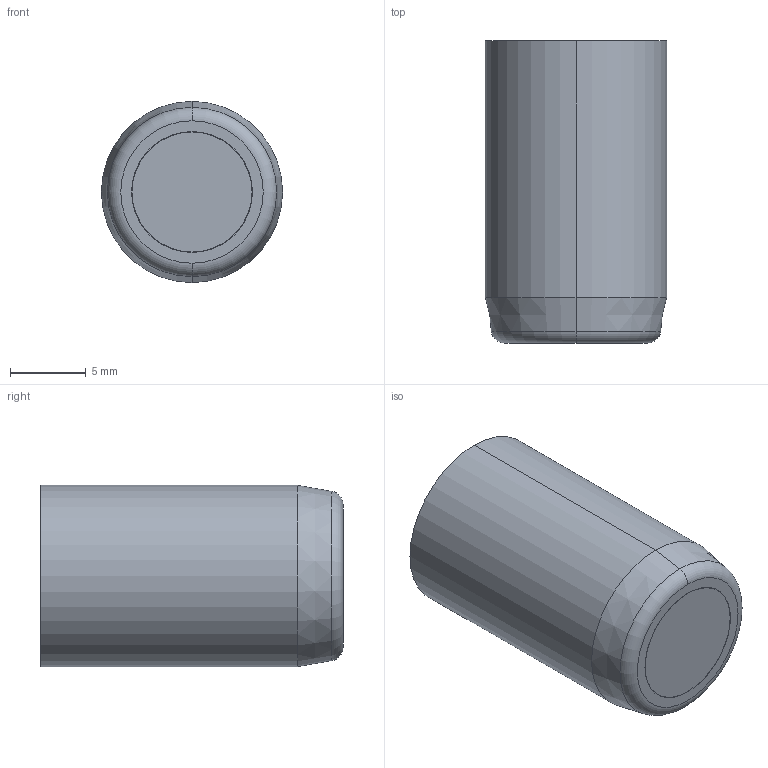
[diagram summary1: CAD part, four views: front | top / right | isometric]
STEP (ISO 10303-21) file: header records copied from the file, then geometry measured from it (millimetres).
FILE_DESCRIPTION (( 'STEP AP214' ), '1' );
FILE_NAME ('FA 126708-20.STEP', '2013-10-01T09:54:28', ( '' ), ( '' ), 'SwSTEP 2.0', 'SolidWorks 2011', '' );
FILE_SCHEMA (( 'AUTOMOTIVE_DESIGN' ));
Length unit declared in the file: millimetre
Products named in the file (6): FA 126700-2 comprimido; FA 126700-1; FA 126708-20; FA 126700-3; IA 6717SF; FA 126708-20-1
Assembly tree (5 placements, depth 2):
  FA 126708-20
    FA 126700-1
    FA 126700-3
    FA 126700-2 comprimido
    FA 126708-20-1
    IA 6717SF
Bounding box: 12 x 20 x 12 mm (x, y, z)
Volume: 2014.6 mm3; surface area: 2188.1 mm2
Topology: 5 solids, 5 shells, 334 faces, 860 edges, 560 vertices
Faces by surface type: plane 149, cylinder 145, cone 24, torus 12, bspline 2, sphere 2
Entity records: 11804 total; most frequent: CARTESIAN_POINT 3130, DIRECTION 1844, ORIENTED_EDGE 1716, EDGE_CURVE 858, AXIS2_PLACEMENT_3D 682, VERTEX_POINT 560, LINE 480, VECTOR 480
One B-rep face of a CAD part: STEP entity #173.
In plain terms, the cylindrical face has radius 6 mm (diameter 12 mm), a partial arc.
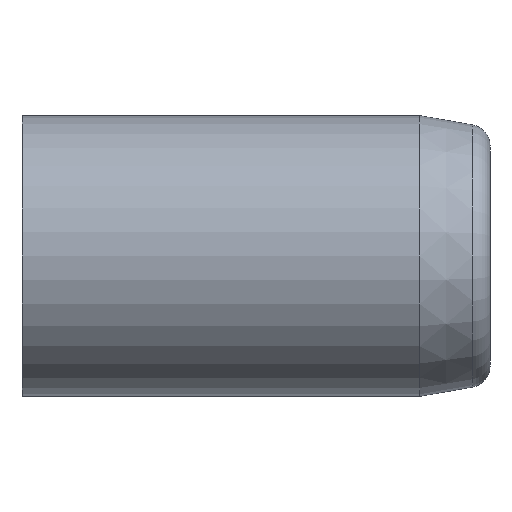
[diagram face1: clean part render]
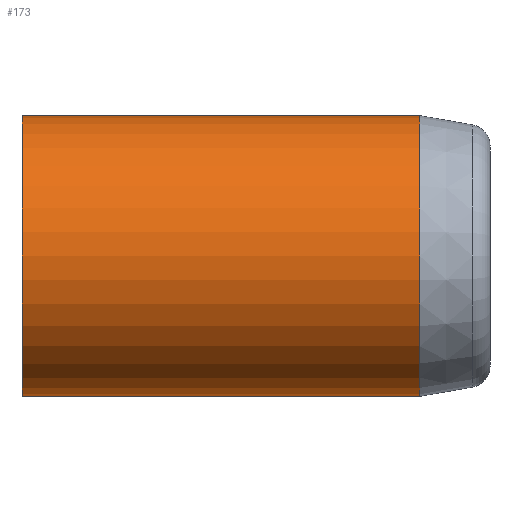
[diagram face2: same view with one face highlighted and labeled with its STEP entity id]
Its self-contained STEP definition (entity closure, numbers rounded to 3 decimals):
#173 = ADVANCED_FACE ( 'NONE', ( #3904 ), #3896, .T. ) ;
#327 = CARTESIAN_POINT ( 'NONE',  ( 0., 10., 0. ) ) ;
#353 = DIRECTION ( 'NONE',  ( 0., -1., 0. ) ) ;
#354 = DIRECTION ( 'NONE',  ( 0., 0., 1. ) ) ;
#1308 = EDGE_CURVE ( 'NONE', #11206, #11200, #6523, .T. ) ;
#1452 = EDGE_CURVE ( 'NONE', #11199, #11145, #1533, .T. ) ;
#1520 = AXIS2_PLACEMENT_3D ( 'NONE', #327, #353, #354 ) ;
#1533 = CIRCLE ( 'NONE', #1520, 6. ) ;
#3861 = CARTESIAN_POINT ( 'NONE',  ( 0., -15., 0. ) ) ;
#3882 = DIRECTION ( 'NONE',  ( 0., 0., 1. ) ) ;
#3892 = DIRECTION ( 'NONE',  ( 0., 1., 0. ) ) ;
#3896 = CYLINDRICAL_SURFACE ( 'NONE', #5238, 6. ) ;
#3904 = FACE_OUTER_BOUND ( 'NONE', #10774, .T. ) ;
#5238 = AXIS2_PLACEMENT_3D ( 'NONE', #3861, #3892, #3882 ) ;
#6413 = VECTOR ( 'NONE', #8782, 1000. ) ;
#6438 = VECTOR ( 'NONE', #8738, 1000. ) ;
#6523 = CIRCLE ( 'NONE', #6525, 6. ) ;
#6525 = AXIS2_PLACEMENT_3D ( 'NONE', #7007, #6982, #7008 ) ;
#6982 = DIRECTION ( 'NONE',  ( 0., 1., 0. ) ) ;
#7007 = CARTESIAN_POINT ( 'NONE',  ( 0., -7., 0. ) ) ;
#7008 = DIRECTION ( 'NONE',  ( 0., 0., -1. ) ) ;
#7268 = CARTESIAN_POINT ( 'NONE',  ( 0., -7., 6. ) ) ;
#7270 = CARTESIAN_POINT ( 'NONE',  ( 0., -7., -6. ) ) ;
#7277 = CARTESIAN_POINT ( 'NONE',  ( 0., 10., 6. ) ) ;
#7601 = CARTESIAN_POINT ( 'NONE',  ( 0., 10., -6. ) ) ;
#8722 = LINE ( 'NONE', #8736, #6438 ) ;
#8736 = CARTESIAN_POINT ( 'NONE',  ( 0., -15., 6. ) ) ;
#8738 = DIRECTION ( 'NONE',  ( 0., 1., 0. ) ) ;
#8781 = CARTESIAN_POINT ( 'NONE',  ( 0., -15., -6. ) ) ;
#8782 = DIRECTION ( 'NONE',  ( 0., 1., 0. ) ) ;
#8787 = LINE ( 'NONE', #8781, #6413 ) ;
#9847 = ORIENTED_EDGE ( 'NONE', *, *, #10636, .T. ) ;
#9864 = ORIENTED_EDGE ( 'NONE', *, *, #1452, .T. ) ;
#9935 = ORIENTED_EDGE ( 'NONE', *, *, #10652, .F. ) ;
#9938 = ORIENTED_EDGE ( 'NONE', *, *, #1308, .T. ) ;
#10636 = EDGE_CURVE ( 'NONE', #11200, #11199, #8722, .T. ) ;
#10652 = EDGE_CURVE ( 'NONE', #11206, #11145, #8787, .T. ) ;
#10774 = EDGE_LOOP ( 'NONE', ( #9935, #9938, #9847, #9864 ) ) ;
#11145 = VERTEX_POINT ( 'NONE', #7601 ) ;
#11199 = VERTEX_POINT ( 'NONE', #7277 ) ;
#11200 = VERTEX_POINT ( 'NONE', #7268 ) ;
#11206 = VERTEX_POINT ( 'NONE', #7270 ) ;
